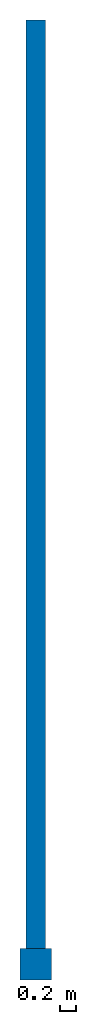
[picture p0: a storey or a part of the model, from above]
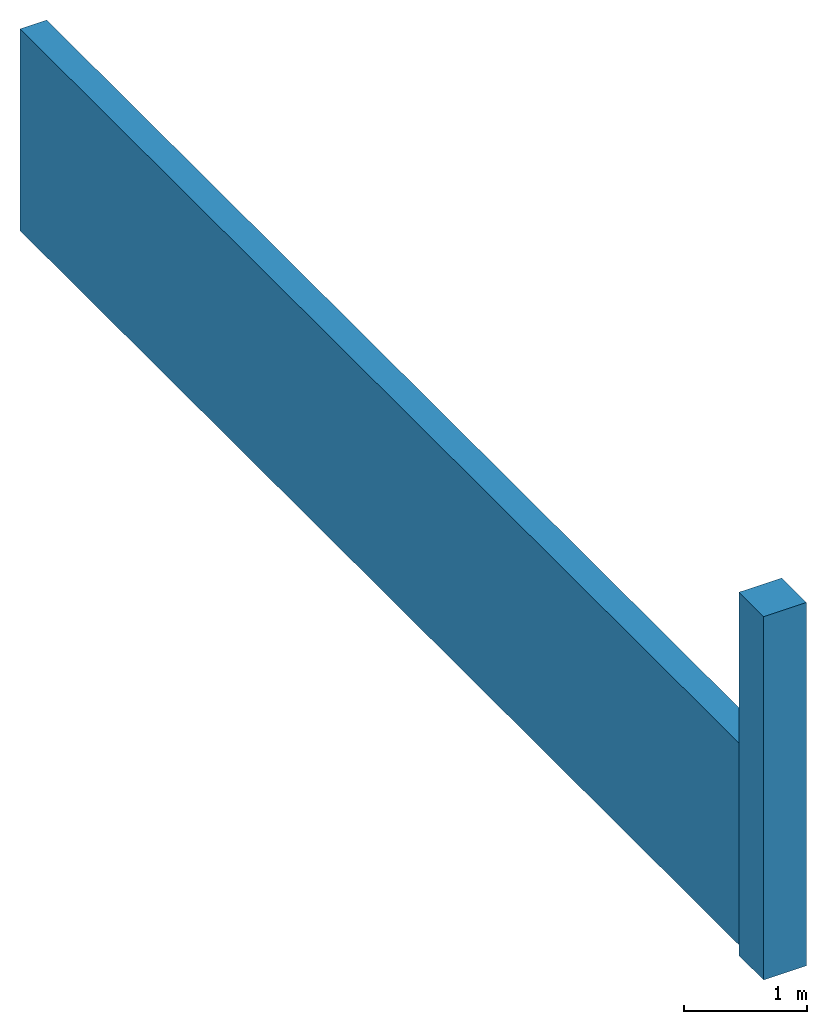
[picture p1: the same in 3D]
Properties of the parts of a building model (IFC2X3)

# File
Description: ViewDefinition[CoordinationView_V2.0, QuantityTakeOffAddOnView], Option [BaseQuantities:On], Option [GridExport:On], Option [Assemblies:On], Option [Bolts:On], Option [Rebars:On], Option [PourObjects:Off], Option [Welds:On], Option [SurfaceTreatments:On], Option [LocationBy:0], Option [ViewColors:On], Option [SectionedSpine:Off], Option [PropertySets:On], Option [Export all:Off]
File name: betão.ifc
Time: 2021-05-31T18:29:08
Author: DESKTOP-JK8PV89\luisa
Organization: Structural Designer
Written by: IFC Database Version: Work
Made in: Tekla Structures Educational 2020 Service Pack 3, IFC Export Version: 4.0.0.0 Sep 22 2020

# IfcBuildingStorey, Undefined
In: Undefined
Elevation: 0 mm

# IfcColumn: 400X400, PILAR
In: Undefined
Description: 400X400; Material: CONCRETE/C20/25
Trimble Connect - MATERIAL: C20/25; PROFILE: 400X400; PART_POS: P0(?); ASSEMBLY_POS: P0(?)
Tekla Common - Bottom elevation: +0.000; Top elevation: +3.600; Phase: 1; Class: 13
Tekla Quantity - Weight: 1382.4 kg; Volume: 0.6 m3; Gross footprint area: 0.2 m2; Area per tons: 4.4 m2; Net surface area: 6.1 m2; Height: 400 mm; Width: 400 mm; Length: 3600 mm
Pset_ColumnCommon - LoadBearing: no; Reference: P0(?)
BaseQuantities - Length: 3600 mm; OuterSurfaceArea: 6.08 m2; NetVolume: 0.576 m3; NetWeight: 1382.4 kg

# IfcElementAssembly (2)
In: Undefined
PredefinedType: REINFORCEMENT_UNIT
Tekla Assembly - Cast unit type: Cast in place; Cast unit rebar weight: 0 kg; Assembly/Cast unit bottom elevation: +0.000
Name | Assembly/Cast unit weight (kg) | Assembly/Cast unit top elevation | Assembly/Cast unit position code | Assembly/Cast unit Mark | Width (mm)
PAREDE | 14400 | +2.000 | 1/A-E | PA0(?) | 250
PILAR | 1382.4 | +3.600 | 1/A | P0(?) | 400

# IfcWall: 250X2000, PAREDE
In: Undefined
Description: 250X2000; Material: CONCRETE/C20/25
Tekla Common - Bottom elevation: +0.000; Top elevation: +2.000; Phase: 1; Class: 5
Tekla Quantity - Weight: 14400 kg; Volume: 6 m3; Gross footprint area: 3 m2; Area per tons: 3.8 m2; Net surface area: 55 m2; Height: 2000 mm; Width: 250 mm; Length: 12000 mm
Pset_WallCommon - LoadBearing: no; Reference: PA0(?)
BaseQuantities - Length: 12000 mm; OuterSurfaceArea: 55 m2; NetVolume: 6 m3; NetWeight: 14400 kg; Width: 250 mm; GrossFootprintArea: 3 m2
